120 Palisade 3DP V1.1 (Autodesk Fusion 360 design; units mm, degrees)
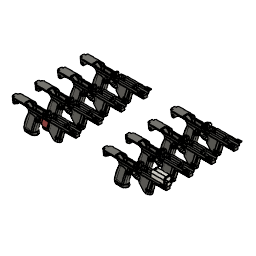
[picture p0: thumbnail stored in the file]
description: Part Number
part number: PDW for CNC v1
part number: 91290A180_Black-Oxide Alloy Steel Socket Head Screw
part number: Component26
part number: 91290A224_Black-Oxide Alloy Steel Socket Head Screw
part number: Trigger Guard Storage Holster (optional)
part number: 98404A103_18-8 Stainless Steel Ring-Grip Quick-Release Pin
base_feature "Base Feature1" bodies "Pin Safety - Lanyard Loop", "Pin Safety - Plain", "Pin Safety - Ambi QD Cups - Free Rotate", "Pin Safety - Ambi QD Cups - Anti Rotate", "No Safety - Ambi QD Cups - Anti Rotate - Trigger Guard Cover Optional", "No Safety - Lanyard Loop - Trigger Guard Cover Optional", "No Safety - Ambi QD Cups - Free Rotate - Trigger Guard Cover Optional", "No Safety - Plain - Trigger Guard Cover Optional"
base_feature "Base Feature1"
base_feature "Base Feature1"
base_feature "Base Feature1"
base_feature "Base Feature1"
base_feature "Base Feature1"
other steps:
create_component "CreateComponent1"
create_component "CreateComponent2"
create_component "CreateComponent3"
create_component "CreateComponent4"
create_component "CreateComponent5"
named bodies: "Pin Safety - Lanyard Loop", "Pin Safety - Plain", "Pin Safety - Ambi QD Cups - Free Rotate", "Pin Safety - Ambi QD Cups - Anti Rotate", "No Safety - Ambi QD Cups - Anti Rotate - Trigger Guard Cover Optional", "No Safety - Lanyard Loop - Trigger Guard Cover Optional", "No Safety - Ambi QD Cups - Free Rotate - Trigger Guard Cover Optional", "No Safety - Plain - Trigger Guard Cover Optional"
